VERSION 5.6 ;
  BUSBITCHARS "[]" ;
  DIVIDERCHAR "/" ;

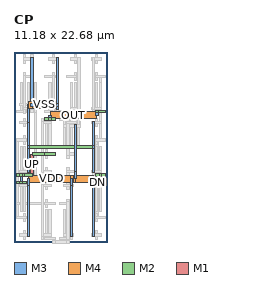
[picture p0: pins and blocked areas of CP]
MACRO CP
  ORIGIN 0 0 ;
  FOREIGN CP 0 0 ;
  SIZE 11.18 BY 22.68 ;
  PIN VSS
    DIRECTION INOUT ;
    USE SIGNAL ;
    PORT 
      LAYER M3 ;
        RECT 2.01 16.22 2.29 22 ;
      LAYER M3 ;
        RECT 1.58 8.24 1.86 14.44 ;
      LAYER M3 ;
        RECT 9.32 8.24 9.6 14.44 ;
      LAYER M3 ;
        RECT 5.02 15.8 5.3 22 ;
      LAYER M3 ;
        RECT 2.01 16.195 2.29 16.565 ;
      LAYER M4 ;
        RECT 1.72 15.98 2.15 16.78 ;
      LAYER M3 ;
        RECT 1.58 14.28 1.86 16.38 ;
      LAYER M3 ;
        RECT 1.58 11.155 1.86 11.525 ;
      LAYER M2 ;
        RECT 1.72 11.2 9.46 11.48 ;
      LAYER M3 ;
        RECT 9.32 11.155 9.6 11.525 ;
      LAYER M4 ;
        RECT 2.15 15.98 5.16 16.78 ;
      LAYER M3 ;
        RECT 5.02 16.195 5.3 16.565 ;
    END
  END VSS
  PIN VDD
    DIRECTION INOUT ;
    USE SIGNAL ;
    PORT 
      LAYER M3 ;
        RECT 7.17 8.24 7.45 14.02 ;
      LAYER M3 ;
        RECT 1.58 0.68 1.86 6.88 ;
      LAYER M3 ;
        RECT 9.32 0.68 9.6 6.88 ;
      LAYER M3 ;
        RECT 6.74 0.68 7.02 6.88 ;
      LAYER M3 ;
        RECT 7.17 7.56 7.45 8.4 ;
      LAYER M4 ;
        RECT 1.72 7.16 7.31 7.96 ;
      LAYER M3 ;
        RECT 1.58 6.72 1.86 7.56 ;
      LAYER M4 ;
        RECT 7.4 7.16 9.46 7.96 ;
      LAYER M3 ;
        RECT 9.32 6.72 9.6 7.56 ;
      LAYER M4 ;
        RECT 6.715 7.16 7.045 7.96 ;
      LAYER M3 ;
        RECT 6.74 6.72 7.02 7.56 ;
    END
  END VDD
  PIN UP
    DIRECTION INOUT ;
    USE SIGNAL ;
    PORT 
      LAYER M2 ;
        RECT 0.26 7.84 1.46 8.12 ;
      LAYER M2 ;
        RECT 0.26 7 1.46 7.28 ;
      LAYER M2 ;
        RECT 0.7 7.84 1.02 8.12 ;
      LAYER M3 ;
        RECT 0.72 7.14 1 7.98 ;
      LAYER M2 ;
        RECT 0.7 7 1.02 7.28 ;
      LAYER M2 ;
        RECT 3.7 10.36 4.9 10.64 ;
      LAYER M2 ;
        RECT 1.29 7.84 2.15 8.12 ;
      LAYER M1 ;
        RECT 2.025 7.98 2.275 10.5 ;
      LAYER M2 ;
        RECT 2.15 10.36 3.87 10.64 ;
    END
  END UP
  PIN DN
    DIRECTION INOUT ;
    USE SIGNAL ;
    PORT 
      LAYER M2 ;
        RECT 9.72 7.84 10.92 8.12 ;
      LAYER M2 ;
        RECT 9.72 7 10.92 7.28 ;
      LAYER M2 ;
        RECT 10.16 7.84 10.48 8.12 ;
      LAYER M3 ;
        RECT 10.18 7.14 10.46 7.98 ;
      LAYER M2 ;
        RECT 10.16 7 10.48 7.28 ;
    END
  END DN
  PIN OUT
    DIRECTION INOUT ;
    USE SIGNAL ;
    PORT 
      LAYER M2 ;
        RECT 3.7 14.56 4.9 14.84 ;
      LAYER M2 ;
        RECT 9.72 15.4 10.92 15.68 ;
      LAYER M2 ;
        RECT 4.14 14.56 4.46 14.84 ;
      LAYER M3 ;
        RECT 4.16 14.7 4.44 15.12 ;
      LAYER M4 ;
        RECT 4.3 14.72 9.89 15.52 ;
      LAYER M3 ;
        RECT 9.75 15.12 10.03 15.54 ;
      LAYER M2 ;
        RECT 9.73 15.4 10.05 15.68 ;
    END
  END OUT
  OBS 
  LAYER M3 ;
        RECT 1.15 15.38 1.43 19.9 ;
  LAYER M2 ;
        RECT 1.12 15.82 2.32 16.1 ;
  LAYER M3 ;
        RECT 3.3 0.68 3.58 6.88 ;
  LAYER M3 ;
        RECT 3.3 8.24 3.58 14.44 ;
  LAYER M2 ;
        RECT 2.15 15.82 2.58 16.1 ;
  LAYER M3 ;
        RECT 2.44 7.56 2.72 15.96 ;
  LAYER M2 ;
        RECT 2.58 7.42 3.44 7.7 ;
  LAYER M3 ;
        RECT 3.3 6.72 3.58 7.56 ;
  LAYER M3 ;
        RECT 3.3 7.56 3.58 8.4 ;
  LAYER M2 ;
        RECT 2.42 7.42 2.74 7.7 ;
  LAYER M3 ;
        RECT 2.44 7.4 2.72 7.72 ;
  LAYER M2 ;
        RECT 2.42 15.82 2.74 16.1 ;
  LAYER M3 ;
        RECT 2.44 15.8 2.72 16.12 ;
  LAYER M2 ;
        RECT 3.28 7.42 3.6 7.7 ;
  LAYER M3 ;
        RECT 3.3 7.4 3.58 7.72 ;
  LAYER M2 ;
        RECT 2.42 7.42 2.74 7.7 ;
  LAYER M3 ;
        RECT 2.44 7.4 2.72 7.72 ;
  LAYER M2 ;
        RECT 2.42 15.82 2.74 16.1 ;
  LAYER M3 ;
        RECT 2.44 15.8 2.72 16.12 ;
  LAYER M2 ;
        RECT 3.28 7.42 3.6 7.7 ;
  LAYER M3 ;
        RECT 3.3 7.4 3.58 7.72 ;
  LAYER M2 ;
        RECT 2.42 7.42 2.74 7.7 ;
  LAYER M3 ;
        RECT 2.44 7.4 2.72 7.72 ;
  LAYER M2 ;
        RECT 2.42 15.82 2.74 16.1 ;
  LAYER M3 ;
        RECT 2.44 15.8 2.72 16.12 ;
  LAYER M2 ;
        RECT 3.28 7.42 3.6 7.7 ;
  LAYER M3 ;
        RECT 3.3 7.4 3.58 7.72 ;
  LAYER M2 ;
        RECT 2.42 7.42 2.74 7.7 ;
  LAYER M3 ;
        RECT 2.44 7.4 2.72 7.72 ;
  LAYER M2 ;
        RECT 2.42 15.82 2.74 16.1 ;
  LAYER M3 ;
        RECT 2.44 15.8 2.72 16.12 ;
  LAYER M2 ;
        RECT 3.28 7.42 3.6 7.7 ;
  LAYER M3 ;
        RECT 3.3 7.4 3.58 7.72 ;
  LAYER M3 ;
        RECT 6.31 10.34 6.59 14.86 ;
  LAYER M2 ;
        RECT 6.28 14.14 7.48 14.42 ;
  LAYER M3 ;
        RECT 9.32 15.8 9.6 22 ;
  LAYER M3 ;
        RECT 7.6 15.8 7.88 22 ;
  LAYER M2 ;
        RECT 7.31 14.14 7.74 14.42 ;
  LAYER M3 ;
        RECT 7.6 14.28 7.88 15.12 ;
  LAYER M2 ;
        RECT 7.74 14.98 9.46 15.26 ;
  LAYER M3 ;
        RECT 9.32 15.12 9.6 15.96 ;
  LAYER M3 ;
        RECT 7.6 15.12 7.88 15.96 ;
  LAYER M2 ;
        RECT 7.58 14.14 7.9 14.42 ;
  LAYER M3 ;
        RECT 7.6 14.12 7.88 14.44 ;
  LAYER M2 ;
        RECT 7.58 14.98 7.9 15.26 ;
  LAYER M3 ;
        RECT 7.6 14.96 7.88 15.28 ;
  LAYER M2 ;
        RECT 9.3 14.98 9.62 15.26 ;
  LAYER M3 ;
        RECT 9.32 14.96 9.6 15.28 ;
  LAYER M2 ;
        RECT 7.58 14.14 7.9 14.42 ;
  LAYER M3 ;
        RECT 7.6 14.12 7.88 14.44 ;
  LAYER M2 ;
        RECT 7.58 14.98 7.9 15.26 ;
  LAYER M3 ;
        RECT 7.6 14.96 7.88 15.28 ;
  LAYER M2 ;
        RECT 9.3 14.98 9.62 15.26 ;
  LAYER M3 ;
        RECT 9.32 14.96 9.6 15.28 ;
  LAYER M2 ;
        RECT 7.58 14.14 7.9 14.42 ;
  LAYER M3 ;
        RECT 7.6 14.12 7.88 14.44 ;
  LAYER M2 ;
        RECT 7.58 14.98 7.9 15.26 ;
  LAYER M3 ;
        RECT 7.6 14.96 7.88 15.28 ;
  LAYER M2 ;
        RECT 9.3 14.98 9.62 15.26 ;
  LAYER M3 ;
        RECT 9.32 14.96 9.6 15.28 ;
  LAYER M2 ;
        RECT 7.58 14.14 7.9 14.42 ;
  LAYER M3 ;
        RECT 7.6 14.12 7.88 14.44 ;
  LAYER M2 ;
        RECT 7.58 14.98 7.9 15.26 ;
  LAYER M3 ;
        RECT 7.6 14.96 7.88 15.28 ;
  LAYER M2 ;
        RECT 9.3 14.98 9.62 15.26 ;
  LAYER M3 ;
        RECT 9.32 14.96 9.6 15.28 ;
  LAYER M2 ;
        RECT 0.26 12.04 1.46 12.32 ;
  LAYER M2 ;
        RECT 0.26 2.8 1.46 3.08 ;
  LAYER M2 ;
        RECT 0.27 12.04 0.59 12.32 ;
  LAYER M1 ;
        RECT 0.305 2.94 0.555 12.18 ;
  LAYER M2 ;
        RECT 0.27 2.8 0.59 3.08 ;
  LAYER M2 ;
        RECT 3.7 4.48 4.9 4.76 ;
  LAYER M1 ;
        RECT 0.305 4.535 0.555 4.705 ;
  LAYER M2 ;
        RECT 0.43 4.48 3.87 4.76 ;
  LAYER M1 ;
        RECT 0.305 4.535 0.555 4.705 ;
  LAYER M2 ;
        RECT 0.26 4.48 0.6 4.76 ;
  LAYER M1 ;
        RECT 0.305 4.535 0.555 4.705 ;
  LAYER M2 ;
        RECT 0.26 4.48 0.6 4.76 ;
  LAYER M2 ;
        RECT 9.72 12.04 10.92 12.32 ;
  LAYER M2 ;
        RECT 9.72 2.8 10.92 3.08 ;
  LAYER M2 ;
        RECT 9.73 12.04 10.05 12.32 ;
  LAYER M3 ;
        RECT 9.75 2.94 10.03 12.18 ;
  LAYER M2 ;
        RECT 9.73 2.8 10.05 3.08 ;
  LAYER M2 ;
        RECT 9.72 19.6 10.92 19.88 ;
  LAYER M2 ;
        RECT 10.16 12.04 10.48 12.32 ;
  LAYER M3 ;
        RECT 10.18 12.18 10.46 19.74 ;
  LAYER M2 ;
        RECT 10.16 19.6 10.48 19.88 ;
  LAYER M2 ;
        RECT 10.16 12.04 10.48 12.32 ;
  LAYER M3 ;
        RECT 10.18 12.02 10.46 12.34 ;
  LAYER M2 ;
        RECT 10.16 19.6 10.48 19.88 ;
  LAYER M3 ;
        RECT 10.18 19.58 10.46 19.9 ;
  LAYER M2 ;
        RECT 10.16 12.04 10.48 12.32 ;
  LAYER M3 ;
        RECT 10.18 12.02 10.46 12.34 ;
  LAYER M2 ;
        RECT 10.16 19.6 10.48 19.88 ;
  LAYER M3 ;
        RECT 10.18 19.58 10.46 19.9 ;
  LAYER M3 ;
        RECT 4.59 15.38 4.87 19.9 ;
  LAYER M2 ;
        RECT 6.28 15.4 7.48 15.68 ;
  LAYER M3 ;
        RECT 4.59 15.12 4.87 15.54 ;
  LAYER M2 ;
        RECT 4.73 14.98 5.59 15.26 ;
  LAYER M1 ;
        RECT 5.465 15.12 5.715 15.54 ;
  LAYER M2 ;
        RECT 5.59 15.4 6.45 15.68 ;
  LAYER M1 ;
        RECT 5.465 15.035 5.715 15.205 ;
  LAYER M2 ;
        RECT 5.42 14.98 5.76 15.26 ;
  LAYER M1 ;
        RECT 5.465 15.455 5.715 15.625 ;
  LAYER M2 ;
        RECT 5.42 15.4 5.76 15.68 ;
  LAYER M2 ;
        RECT 4.57 14.98 4.89 15.26 ;
  LAYER M3 ;
        RECT 4.59 14.96 4.87 15.28 ;
  LAYER M1 ;
        RECT 5.465 15.035 5.715 15.205 ;
  LAYER M2 ;
        RECT 5.42 14.98 5.76 15.26 ;
  LAYER M1 ;
        RECT 5.465 15.455 5.715 15.625 ;
  LAYER M2 ;
        RECT 5.42 15.4 5.76 15.68 ;
  LAYER M2 ;
        RECT 4.57 14.98 4.89 15.26 ;
  LAYER M3 ;
        RECT 4.59 14.96 4.87 15.28 ;
  LAYER M3 ;
        RECT 6.31 0.26 6.59 4.78 ;
  LAYER M2 ;
        RECT 3.7 0.28 4.9 0.56 ;
  LAYER M3 ;
        RECT 6.31 0 6.59 0.42 ;
  LAYER M2 ;
        RECT 4.73 -0.14 6.45 0.14 ;
  LAYER M1 ;
        RECT 4.605 0 4.855 0.42 ;
  LAYER M2 ;
        RECT 4.57 0.28 4.89 0.56 ;
  LAYER M1 ;
        RECT 4.605 -0.085 4.855 0.085 ;
  LAYER M2 ;
        RECT 4.56 -0.14 4.9 0.14 ;
  LAYER M1 ;
        RECT 4.605 0.335 4.855 0.505 ;
  LAYER M2 ;
        RECT 4.56 0.28 4.9 0.56 ;
  LAYER M2 ;
        RECT 6.29 -0.14 6.61 0.14 ;
  LAYER M3 ;
        RECT 6.31 -0.16 6.59 0.16 ;
  LAYER M1 ;
        RECT 4.605 -0.085 4.855 0.085 ;
  LAYER M2 ;
        RECT 4.56 -0.14 4.9 0.14 ;
  LAYER M1 ;
        RECT 4.605 0.335 4.855 0.505 ;
  LAYER M2 ;
        RECT 4.56 0.28 4.9 0.56 ;
  LAYER M2 ;
        RECT 6.29 -0.14 6.61 0.14 ;
  LAYER M3 ;
        RECT 6.31 -0.16 6.59 0.16 ;
  LAYER M2 ;
        RECT 6.28 19.6 7.48 19.88 ;
  LAYER M1 ;
        RECT 1.165 15.455 1.415 18.985 ;
  LAYER M1 ;
        RECT 1.165 19.235 1.415 20.245 ;
  LAYER M1 ;
        RECT 1.165 21.335 1.415 22.345 ;
  LAYER M1 ;
        RECT 0.735 15.455 0.985 18.985 ;
  LAYER M1 ;
        RECT 1.595 15.455 1.845 18.985 ;
  LAYER M1 ;
        RECT 2.025 15.455 2.275 18.985 ;
  LAYER M1 ;
        RECT 2.025 19.235 2.275 20.245 ;
  LAYER M1 ;
        RECT 2.025 21.335 2.275 22.345 ;
  LAYER M1 ;
        RECT 2.455 15.455 2.705 18.985 ;
  LAYER M2 ;
        RECT 1.12 19.6 2.32 19.88 ;
  LAYER M2 ;
        RECT 0.26 15.4 1.46 15.68 ;
  LAYER M2 ;
        RECT 1.12 21.7 2.32 21.98 ;
  LAYER M2 ;
        RECT 0.69 16.24 2.75 16.52 ;
  LAYER M3 ;
        RECT 1.15 15.38 1.43 19.9 ;
  LAYER M2 ;
        RECT 1.12 15.82 2.32 16.1 ;
  LAYER M3 ;
        RECT 2.01 16.22 2.29 22 ;
  LAYER M1 ;
        RECT 6.325 11.255 6.575 14.785 ;
  LAYER M1 ;
        RECT 6.325 9.995 6.575 11.005 ;
  LAYER M1 ;
        RECT 6.325 7.895 6.575 8.905 ;
  LAYER M1 ;
        RECT 5.895 11.255 6.145 14.785 ;
  LAYER M1 ;
        RECT 6.755 11.255 7.005 14.785 ;
  LAYER M1 ;
        RECT 7.185 11.255 7.435 14.785 ;
  LAYER M1 ;
        RECT 7.185 9.995 7.435 11.005 ;
  LAYER M1 ;
        RECT 7.185 7.895 7.435 8.905 ;
  LAYER M1 ;
        RECT 7.615 11.255 7.865 14.785 ;
  LAYER M2 ;
        RECT 6.28 10.36 7.48 10.64 ;
  LAYER M2 ;
        RECT 5.42 14.56 6.62 14.84 ;
  LAYER M2 ;
        RECT 6.28 8.26 7.48 8.54 ;
  LAYER M2 ;
        RECT 5.85 13.72 7.91 14 ;
  LAYER M3 ;
        RECT 6.31 10.34 6.59 14.86 ;
  LAYER M2 ;
        RECT 6.28 14.14 7.48 14.42 ;
  LAYER M3 ;
        RECT 7.17 8.24 7.45 14.02 ;
  LAYER M1 ;
        RECT 1.165 7.895 1.415 11.425 ;
  LAYER M1 ;
        RECT 1.165 11.675 1.415 12.685 ;
  LAYER M1 ;
        RECT 1.165 13.775 1.415 14.785 ;
  LAYER M1 ;
        RECT 0.735 7.895 0.985 11.425 ;
  LAYER M1 ;
        RECT 1.595 7.895 1.845 11.425 ;
  LAYER M2 ;
        RECT 0.69 14.14 1.89 14.42 ;
  LAYER M2 ;
        RECT 0.69 8.26 1.89 8.54 ;
  LAYER M2 ;
        RECT 0.26 7.84 1.46 8.12 ;
  LAYER M2 ;
        RECT 0.26 12.04 1.46 12.32 ;
  LAYER M3 ;
        RECT 1.58 8.24 1.86 14.44 ;
  LAYER M1 ;
        RECT 1.165 3.695 1.415 7.225 ;
  LAYER M1 ;
        RECT 1.165 2.435 1.415 3.445 ;
  LAYER M1 ;
        RECT 1.165 0.335 1.415 1.345 ;
  LAYER M1 ;
        RECT 0.735 3.695 0.985 7.225 ;
  LAYER M1 ;
        RECT 1.595 3.695 1.845 7.225 ;
  LAYER M2 ;
        RECT 0.69 0.7 1.89 0.98 ;
  LAYER M2 ;
        RECT 0.69 6.58 1.89 6.86 ;
  LAYER M2 ;
        RECT 0.26 7 1.46 7.28 ;
  LAYER M2 ;
        RECT 0.26 2.8 1.46 3.08 ;
  LAYER M3 ;
        RECT 1.58 0.68 1.86 6.88 ;
  LAYER M1 ;
        RECT 9.765 7.895 10.015 11.425 ;
  LAYER M1 ;
        RECT 9.765 11.675 10.015 12.685 ;
  LAYER M1 ;
        RECT 9.765 13.775 10.015 14.785 ;
  LAYER M1 ;
        RECT 10.195 7.895 10.445 11.425 ;
  LAYER M1 ;
        RECT 9.335 7.895 9.585 11.425 ;
  LAYER M2 ;
        RECT 9.29 14.14 10.49 14.42 ;
  LAYER M2 ;
        RECT 9.29 8.26 10.49 8.54 ;
  LAYER M2 ;
        RECT 9.72 7.84 10.92 8.12 ;
  LAYER M2 ;
        RECT 9.72 12.04 10.92 12.32 ;
  LAYER M3 ;
        RECT 9.32 8.24 9.6 14.44 ;
  LAYER M1 ;
        RECT 9.765 3.695 10.015 7.225 ;
  LAYER M1 ;
        RECT 9.765 2.435 10.015 3.445 ;
  LAYER M1 ;
        RECT 9.765 0.335 10.015 1.345 ;
  LAYER M1 ;
        RECT 10.195 3.695 10.445 7.225 ;
  LAYER M1 ;
        RECT 9.335 3.695 9.585 7.225 ;
  LAYER M2 ;
        RECT 9.29 0.7 10.49 0.98 ;
  LAYER M2 ;
        RECT 9.29 6.58 10.49 6.86 ;
  LAYER M2 ;
        RECT 9.72 7 10.92 7.28 ;
  LAYER M2 ;
        RECT 9.72 2.8 10.92 3.08 ;
  LAYER M3 ;
        RECT 9.32 0.68 9.6 6.88 ;
  LAYER M1 ;
        RECT 4.605 15.455 4.855 18.985 ;
  LAYER M1 ;
        RECT 4.605 19.235 4.855 20.245 ;
  LAYER M1 ;
        RECT 4.605 21.335 4.855 22.345 ;
  LAYER M1 ;
        RECT 4.175 15.455 4.425 18.985 ;
  LAYER M1 ;
        RECT 5.035 15.455 5.285 18.985 ;
  LAYER M2 ;
        RECT 3.7 19.6 4.9 19.88 ;
  LAYER M2 ;
        RECT 3.7 15.4 4.9 15.68 ;
  LAYER M2 ;
        RECT 4.13 21.7 5.33 21.98 ;
  LAYER M2 ;
        RECT 4.13 15.82 5.33 16.1 ;
  LAYER M3 ;
        RECT 4.59 15.38 4.87 19.9 ;
  LAYER M3 ;
        RECT 5.02 15.8 5.3 22 ;
  LAYER M1 ;
        RECT 6.325 0.335 6.575 3.865 ;
  LAYER M1 ;
        RECT 6.325 4.115 6.575 5.125 ;
  LAYER M1 ;
        RECT 6.325 6.215 6.575 7.225 ;
  LAYER M1 ;
        RECT 5.895 0.335 6.145 3.865 ;
  LAYER M1 ;
        RECT 6.755 0.335 7.005 3.865 ;
  LAYER M2 ;
        RECT 5.42 4.48 6.62 4.76 ;
  LAYER M2 ;
        RECT 5.42 0.28 6.62 0.56 ;
  LAYER M2 ;
        RECT 5.85 6.58 7.05 6.86 ;
  LAYER M2 ;
        RECT 5.85 0.7 7.05 0.98 ;
  LAYER M3 ;
        RECT 6.31 0.26 6.59 4.78 ;
  LAYER M3 ;
        RECT 6.74 0.68 7.02 6.88 ;
  LAYER M1 ;
        RECT 3.745 0.335 3.995 3.865 ;
  LAYER M1 ;
        RECT 3.745 4.115 3.995 5.125 ;
  LAYER M1 ;
        RECT 3.745 6.215 3.995 7.225 ;
  LAYER M1 ;
        RECT 4.175 0.335 4.425 3.865 ;
  LAYER M1 ;
        RECT 3.315 0.335 3.565 3.865 ;
  LAYER M2 ;
        RECT 3.27 6.58 4.47 6.86 ;
  LAYER M2 ;
        RECT 3.27 0.7 4.47 0.98 ;
  LAYER M2 ;
        RECT 3.7 0.28 4.9 0.56 ;
  LAYER M2 ;
        RECT 3.7 4.48 4.9 4.76 ;
  LAYER M3 ;
        RECT 3.3 0.68 3.58 6.88 ;
  LAYER M1 ;
        RECT 3.745 11.255 3.995 14.785 ;
  LAYER M1 ;
        RECT 3.745 9.995 3.995 11.005 ;
  LAYER M1 ;
        RECT 3.745 7.895 3.995 8.905 ;
  LAYER M1 ;
        RECT 4.175 11.255 4.425 14.785 ;
  LAYER M1 ;
        RECT 3.315 11.255 3.565 14.785 ;
  LAYER M2 ;
        RECT 3.27 8.26 4.47 8.54 ;
  LAYER M2 ;
        RECT 3.27 14.14 4.47 14.42 ;
  LAYER M2 ;
        RECT 3.7 14.56 4.9 14.84 ;
  LAYER M2 ;
        RECT 3.7 10.36 4.9 10.64 ;
  LAYER M3 ;
        RECT 3.3 8.24 3.58 14.44 ;
  LAYER M1 ;
        RECT 9.765 15.455 10.015 18.985 ;
  LAYER M1 ;
        RECT 9.765 19.235 10.015 20.245 ;
  LAYER M1 ;
        RECT 9.765 21.335 10.015 22.345 ;
  LAYER M1 ;
        RECT 10.195 15.455 10.445 18.985 ;
  LAYER M1 ;
        RECT 9.335 15.455 9.585 18.985 ;
  LAYER M2 ;
        RECT 9.29 21.7 10.49 21.98 ;
  LAYER M2 ;
        RECT 9.29 15.82 10.49 16.1 ;
  LAYER M2 ;
        RECT 9.72 15.4 10.92 15.68 ;
  LAYER M2 ;
        RECT 9.72 19.6 10.92 19.88 ;
  LAYER M3 ;
        RECT 9.32 15.8 9.6 22 ;
  LAYER M1 ;
        RECT 7.185 15.455 7.435 18.985 ;
  LAYER M1 ;
        RECT 7.185 19.235 7.435 20.245 ;
  LAYER M1 ;
        RECT 7.185 21.335 7.435 22.345 ;
  LAYER M1 ;
        RECT 6.755 15.455 7.005 18.985 ;
  LAYER M1 ;
        RECT 7.615 15.455 7.865 18.985 ;
  LAYER M2 ;
        RECT 6.71 21.7 7.91 21.98 ;
  LAYER M2 ;
        RECT 6.71 15.82 7.91 16.1 ;
  LAYER M2 ;
        RECT 6.28 15.4 7.48 15.68 ;
  LAYER M2 ;
        RECT 6.28 19.6 7.48 19.88 ;
  LAYER M3 ;
        RECT 7.6 15.8 7.88 22 ;
  END 
END CP
END LIBRARY
